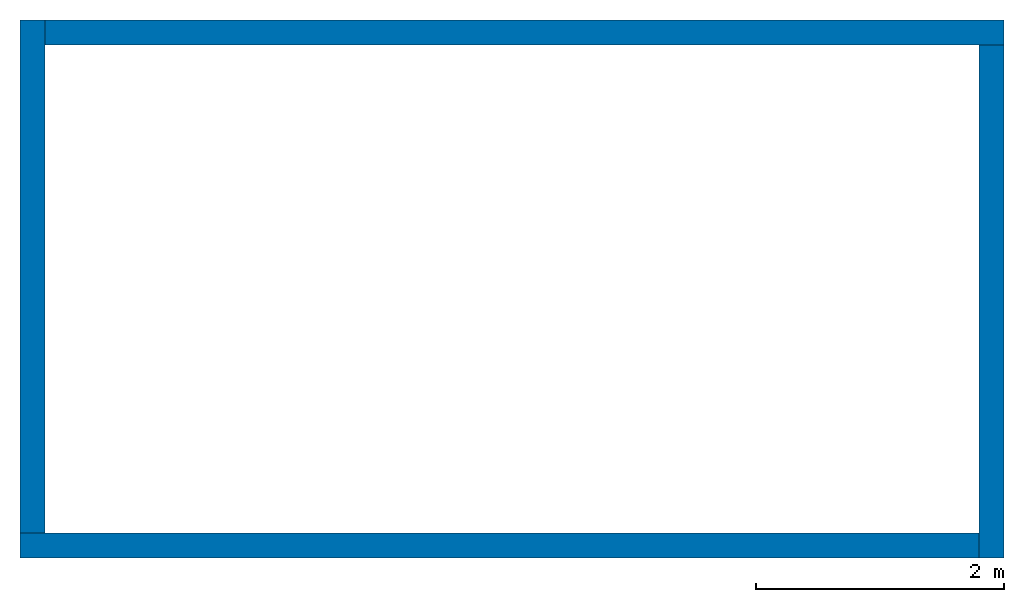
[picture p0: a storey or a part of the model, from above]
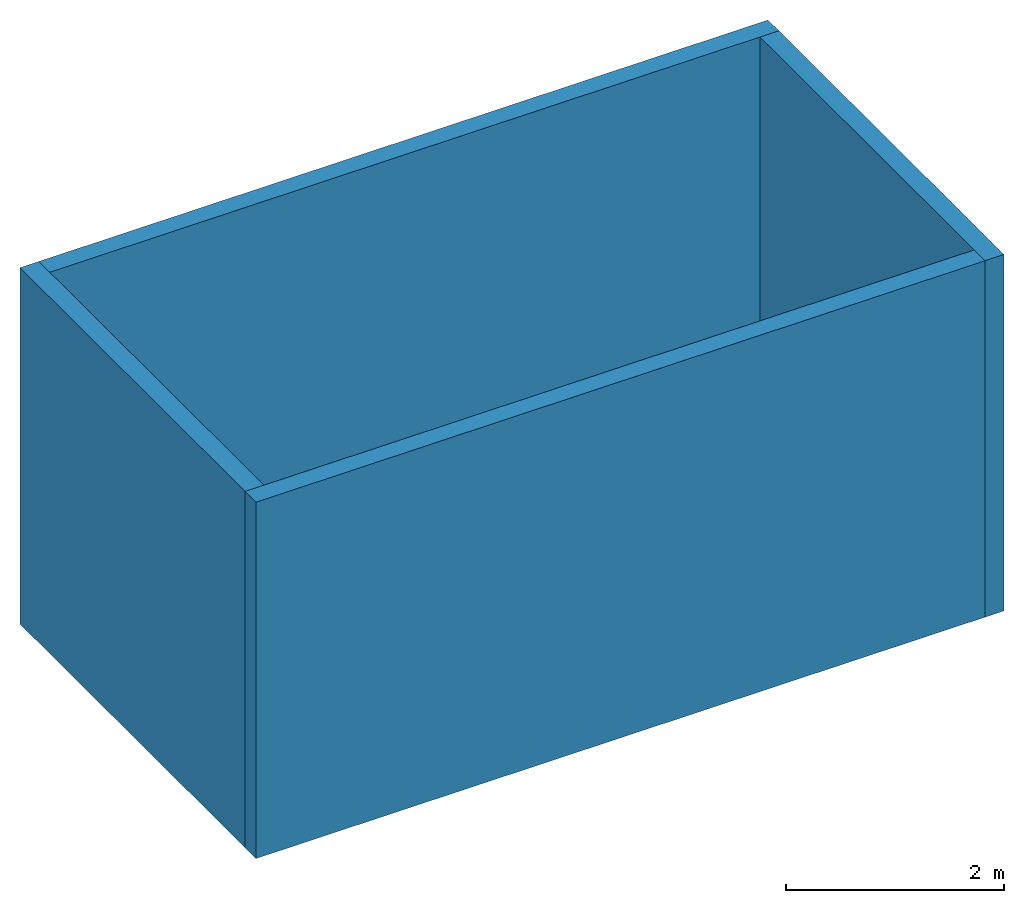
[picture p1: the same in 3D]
Properties of the parts of a building model (IFC2X3)

# File
Description: ViewDefinition [CoordinationView_V2.0]
Time: 2013-12-04T22:39:57
Written by: The EXPRESS Data Manager Version 5.01.0100.02.64mod : 6 Jun 2012
Made in: 20130308_1515(x64) - Exporter 3.5.0.0 - Alternate UI 2.5.0.0
Comment: STEP Physical File produced by: The EXPRESS Data Manager Version 5.01.0100.02.64mod : 6 Jun 2012 * Module: EDMstepFileFactory/EDMstandAlone * Creation date: Wed Dec 04 22:39:57 2013 * Host: MDR_LPTP_BTO * Database: C:\Users\Martijn\AppData\Local\Temp\{A5658229-55F2-4FC8-8E57-92145AF30D8A}\ifc * Database version: 5507 * Database creation date: Wed Dec 04 22:39:55 2013 * Schema: IFC2X3 * Model: DataRepository.ifc * Model creation date: Wed Dec 04 22:39:55 2013 * Header model: DataRepository.ifc_HeaderModel * Header model creation date: Wed Dec 04 22:39:55 2013 * EDMuser: sdai-user * EDMgroup: sdai-group * License ID and type: 5605 : Permanent license. Expiry date: * EDMstepFileFactory options: 020000

# IfcProject
LongName: E:\MdR Advies\Google Drive\001 - Overige werkzaamheden\AU2013\presentation files\test_walls.ifc

# IfcSite, Default
RefLatitude: 42, 24, 53, 508911; RefLongitude: -71, -15, -29, -58837; RefElevation: 0 mm

# IfcBuilding
Pset_BuildingCommon - NumberOfStoreys: 1

# IfcBuildingStorey, Level 1
LongName: Level 1; Elevation: 0 mm

# IfcWallStandardCase: Basic Wall:Wall 1 (4)
In: Level 1
Type - PredefinedType: STANDARD; Material: Default Wall 200 mm
Pset_WallCommon - Reference: Wall 1; LoadBearing: no; ExtendToStructure: no; IsExternal: yes
PSet_COBIE - NominalWidth: 200
Name (Basic Wall:Wall 1:...) | NominalLength
2277 | 7740
2278 | 4140
2279 | 7740
2280 | 4140
